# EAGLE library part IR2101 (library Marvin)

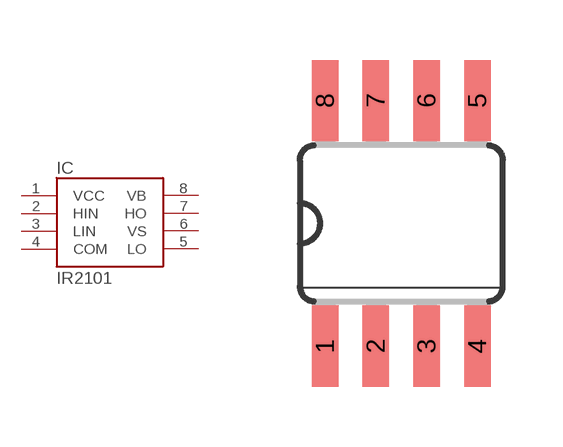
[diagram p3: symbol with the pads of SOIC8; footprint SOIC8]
Designator prefix IC

## IR2101S  [SOIC8]
1  VCC
2  HIN
3  LIN
4  COM
5  LO
6  VS
7  HO
8  VB

## Footprint SOIC8 (pad centres in mm)
smd 0.66 x 2.032: 1 -1.905,-3.073; 2 -0.635,-3.073; 3 0.635,-3.073; 4 1.905,-3.073; 5 1.905,3.073; 6 0.635,3.073; 7 -0.635,3.073; 8 -1.905,3.073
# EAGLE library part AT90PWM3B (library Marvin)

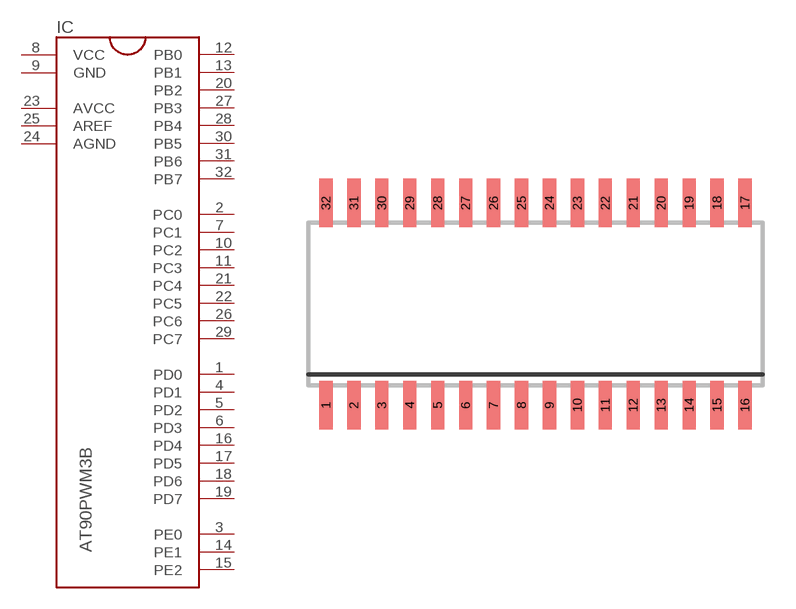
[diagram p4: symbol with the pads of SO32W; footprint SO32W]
Designator prefix IC

## AT90PWM3BS  [SO32W]
1  PD0
2  PC0
3  PE0
4  PD1
5  PD2
6  PD3
7  PC1
8  VCC
9  GND
10  PC2
11  PC3
12  PB0
13  PB1
14  PE1
15  PE2
16  PD4
17  PD5
18  PD6
19  PD7
20  PB2
21  PC4
22  PC5
23  AVCC
24  AGND
25  AREF
26  PC6
27  PB3
28  PB4
29  PC7
30  PB5
31  PB6
32  PB7

## Footprint SO32W (pad centres in mm)
smd 0.6 x 2.2: 1 -9.525,-4.6; 2 -8.255,-4.6; 3 -6.985,-4.6; 4 -5.715,-4.6; 5 -4.445,-4.6; 6 -3.175,-4.6; 7 -1.905,-4.6; 8 -0.635,-4.6; 9 0.635,-4.6; 10 1.905,-4.6; 11 3.175,-4.6; 12 4.445,-4.6; 13 5.715,-4.6; 14 6.985,-4.6; 15 8.255,-4.6; 16 9.525,-4.6; 17 9.525,4.6; 18 8.255,4.6; 19 6.985,4.6; 20 5.715,4.6; 21 4.445,4.6; 22 3.175,4.6; 23 1.905,4.6; 24 0.635,4.6; 25 -0.635,4.6; 26 -1.905,4.6; 27 -3.175,4.6; 28 -4.445,4.6; 29 -5.715,4.6; 30 -6.985,4.6; 31 -8.255,4.6; 32 -9.525,4.6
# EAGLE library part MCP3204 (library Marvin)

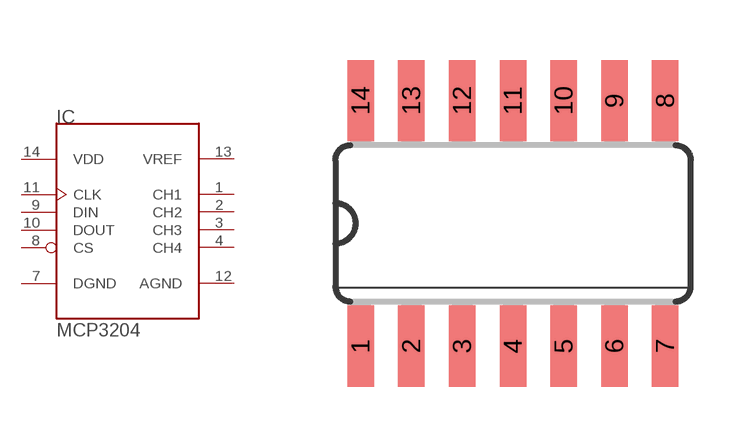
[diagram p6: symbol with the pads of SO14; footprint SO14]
Designator prefix IC

## MCP3204S  [SO14]
1  CH1
2  CH2
3  CH3
4  CH4
7  DGND
8  CS
9  DIN
10  DOUT
11  CLK
12  AGND
13  VREF
14  VDD

## Footprint SO14 (pad centres in mm)
Small Outline package 150 mil
smd 0.66 x 2.032: 1 -3.81,-3.073; 2 -2.54,-3.073; 3 -1.27,-3.073; 4 0,-3.073; 5 1.27,-3.073; 6 2.54,-3.073; 7 3.81,-3.073; 8 3.81,3.073; 9 2.54,3.073; 10 1.27,3.073; 11 0,3.073; 12 -1.27,3.073; 13 -2.54,3.073; 14 -3.81,3.073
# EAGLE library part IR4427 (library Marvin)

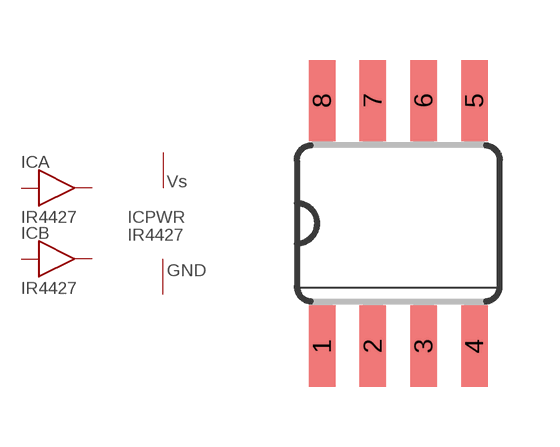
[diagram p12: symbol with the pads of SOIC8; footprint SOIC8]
Designator prefix IC; gates B=IR4427 A=IR4427 PWR=PWR

## IR4427S  [SOIC8]
2  B:IN  in
3  PWR:GND  pwr
4  A:IN  in
5  A:OUT  out
6  PWR:VS  pwr
7  B:OUT  out

## Footprint SOIC8 (pad centres in mm)
smd 0.66 x 2.032: 1 -1.905,-3.073; 2 -0.635,-3.073; 3 0.635,-3.073; 4 1.905,-3.073; 5 1.905,3.073; 6 0.635,3.073; 7 -0.635,3.073; 8 -1.905,3.073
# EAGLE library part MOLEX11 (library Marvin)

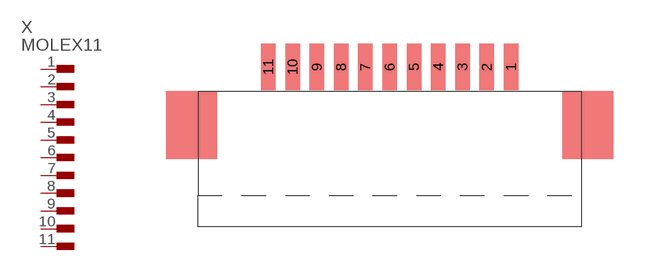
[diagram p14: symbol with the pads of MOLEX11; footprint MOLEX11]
Designator prefix X

## MOLEX11  [MOLEX11]
1  -1
2  -2
3  -3
4  -4
5  -5
6  -6
7  -7
8  -8
9  -9
10  -10
11  -11

## Footprint MOLEX11 (pad centres in mm)
smd 0.6 x 1.9: 1 5,3; 2 4,3; 3 3,3; 4 2,3; 5 1,3; 6 0,3; 7 -1,3; 8 -2,3; 9 -3,3; 10 -4,3; 11 -5,3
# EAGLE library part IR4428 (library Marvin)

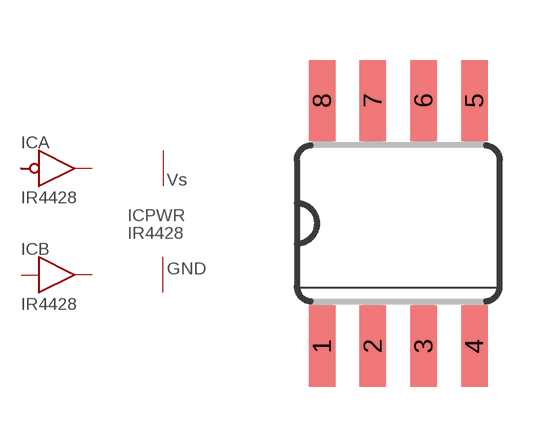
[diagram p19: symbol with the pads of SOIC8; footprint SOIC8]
Designator prefix IC; gates A=AMPN B=AMP PWR=PWR

## IR4428  [SOIC8]
2  A:IN  in
3  PWR:GND  pwr
4  B:IN  in
5  B:OUT  out
6  PWR:VS  pwr
7  A:OUT  out

## Footprint SOIC8 (pad centres in mm)
smd 0.66 x 2.032: 1 -1.905,-3.073; 2 -0.635,-3.073; 3 0.635,-3.073; 4 1.905,-3.073; 5 1.905,3.073; 6 0.635,3.073; 7 -0.635,3.073; 8 -1.905,3.073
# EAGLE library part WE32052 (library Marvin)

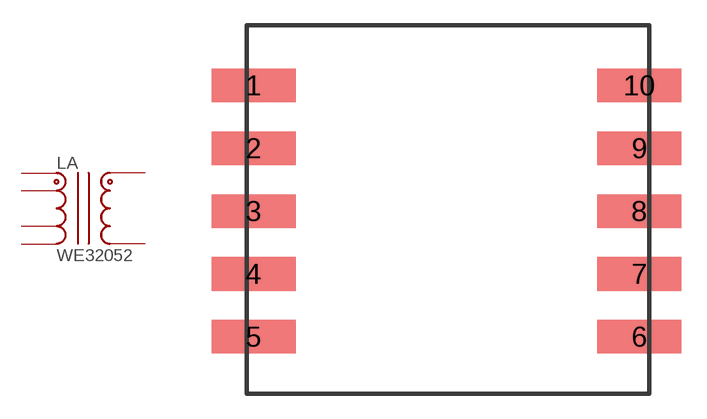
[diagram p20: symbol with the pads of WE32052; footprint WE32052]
Designator prefix L; gates A=FLYBACK-TRANSFORMER B=FLYBACK-TRANSFORMER2

## WE32052  [WE32052]
1  B:1
4  A:4
5  A:5
6  A:6
7  A:7
10  B:10

## Footprint WE32052 (pad centres in mm)
smd 5 x 2: 1 -11.4,7.6; 2 -11.4,3.85; 3 -11.4,0.1; 4 -11.4,-3.65; 5 -11.4,-7.4; 6 11.6,-7.4; 7 11.6,-3.65; 8 11.6,0.1; 9 11.6,3.85; 10 11.6,7.6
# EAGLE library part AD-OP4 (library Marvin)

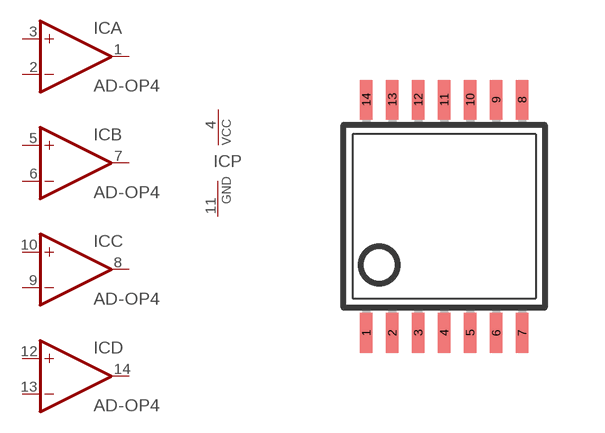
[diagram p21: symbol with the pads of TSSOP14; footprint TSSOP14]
Designator prefix IC; gates A=OP B=OP C=OP D=OP P=PWRGND

## AD-OP4  [TSSOP14]
1  A:OUT  out
2  A:-IN  in
3  A:+IN  in
4  P:VCC  pwr
5  B:+IN  in
6  B:-IN  in
7  B:OUT  out
8  C:OUT  out
9  C:-IN  in
10  C:+IN  in
11  P:GND  pwr
12  D:+IN  in
13  D:-IN  in
14  D:OUT  out

## Footprint TSSOP14 (pad centres in mm)
smd 0.305 x 0.991: 1 -1.95,-2.918; 2 -1.3,-2.918; 3 -0.65,-2.918; 4 0,-2.918; 5 0.65,-2.918; 6 1.3,-2.918; 7 1.95,-2.918; 8 1.95,2.918; 9 1.3,2.918; 10 0.65,2.918; 11 0,2.918; 12 -0.65,2.918; 13 -1.3,2.918; 14 -1.95,2.918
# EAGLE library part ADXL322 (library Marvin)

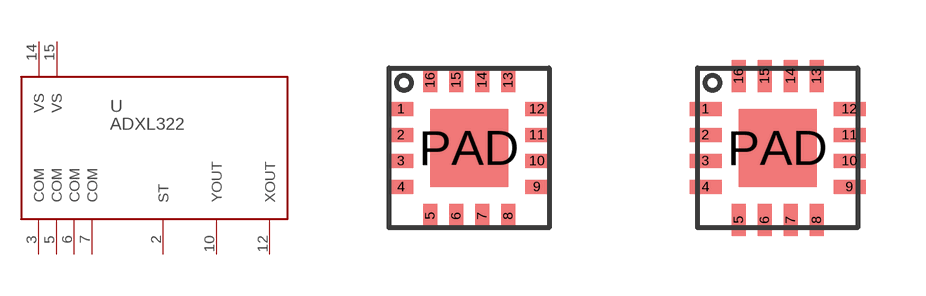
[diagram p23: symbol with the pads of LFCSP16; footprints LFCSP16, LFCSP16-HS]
Designator prefix U

## ADXL322JCP  [LFCSP16]
1  NC  nc
2  ST  in
3  COM  pwr
4  NC  nc
5  COM  pwr
6  COM  pwr
7  COM  pwr
8  NC  nc
9  NC  nc
10  YOUT  out
11  NC  nc
12  XOUT  out
13  NC  nc
14  VS  pwr
15  VS  pwr
16  NC  nc

## ADXL322JCP-HS  [LFCSP16-HS]
Pads as for LFCSP16

## Footprint LFCSP16 (pad centres in mm)
smd 0.6 x 0.35: 1 -1.7,0.975; 2 -1.7,0.325; 3 -1.7,-0.325; 4 -1.7,-0.975; 9 1.7,-0.975; 10 1.7,-0.325; 11 1.7,0.325; 12 1.7,0.975
smd 0.35 x 0.6: 5 -0.975,-1.7; 6 -0.325,-1.7; 7 0.325,-1.7; 8 0.975,-1.7; 13 0.975,1.7; 14 0.325,1.7; 15 -0.325,1.7; 16 -0.975,1.7
smd 1.95 x 1.95: PAD 0,0

## Footprint LFCSP16-HS (pad centres in mm)
smd 0.8 x 0.35: 1 -1.8,0.975; 2 -1.8,0.325; 3 -1.8,-0.325; 4 -1.8,-0.975; 9 1.8,-0.975; 10 1.8,-0.325; 11 1.8,0.325; 12 1.8,0.975
smd 0.35 x 0.8: 5 -0.975,-1.8; 6 -0.325,-1.8; 7 0.325,-1.8; 8 0.975,-1.8; 13 0.975,1.8; 14 0.325,1.8; 15 -0.325,1.8; 16 -0.975,1.8
smd 1.95 x 1.95: PAD 0,0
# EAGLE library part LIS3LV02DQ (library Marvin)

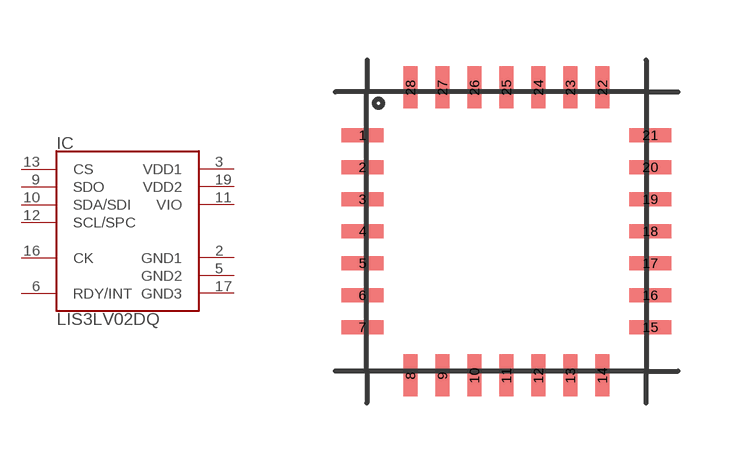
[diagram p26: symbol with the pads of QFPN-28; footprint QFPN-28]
Designator prefix IC

## LIS3LV02DQ  [QFPN-28]
2  GND1
3  VDD1
5  GND2
6  RDY/INT
9  SDO
10  SDA/SDI
11  VIO
12  SCL/SPC
13  CS
16  CK
17  GND3
19  VDD2

## Footprint QFPN-28 (pad centres in mm)
smd 1.05 x 0.35: 1 -3.6,2.4; 2 -3.6,1.6; 3 -3.6,0.8; 4 -3.6,0; 5 -3.6,-0.8; 6 -3.6,-1.6; 7 -3.6,-2.4; 15 3.6,-2.4; 16 3.6,-1.6; 17 3.6,-0.8; 18 3.6,0; 19 3.6,0.8; 20 3.6,1.6; 21 3.6,2.4
smd 0.35 x 1.05: 8 -2.4,-3.6; 9 -1.6,-3.6; 10 -0.8,-3.6; 11 0,-3.6; 12 0.8,-3.6; 13 1.6,-3.6; 14 2.4,-3.6; 22 2.4,3.6; 23 1.6,3.6; 24 0.8,3.6; 25 0,3.6; 26 -0.8,3.6; 27 -1.6,3.6; 28 -2.4,3.6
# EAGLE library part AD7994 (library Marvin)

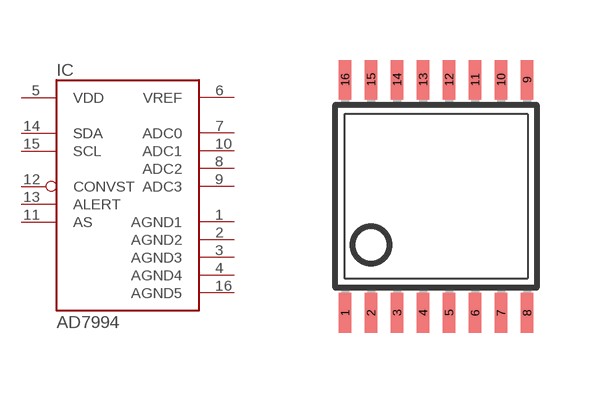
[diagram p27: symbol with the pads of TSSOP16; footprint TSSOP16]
Designator prefix IC

## AD7994  [TSSOP16]
1  AGND1
2  AGND2
3  AGND3
4  AGND4
5  VDD
6  VREF
7  ADC0
8  ADC2
9  ADC3
10  ADC1
11  AS
12  CONVST
13  ALERT
14  SDA
15  SCL
16  AGND5

## Footprint TSSOP16 (pad centres in mm)
smd 0.305 x 0.991: 1 -2.275,-2.918; 2 -1.625,-2.918; 3 -0.975,-2.918; 4 -0.325,-2.918; 5 0.325,-2.918; 6 0.975,-2.918; 7 1.625,-2.918; 8 2.275,-2.918; 9 2.275,2.918; 10 1.625,2.918; 11 0.975,2.918; 12 0.325,2.918; 13 -0.325,2.918; 14 -0.975,2.918; 15 -1.625,2.918; 16 -2.275,2.918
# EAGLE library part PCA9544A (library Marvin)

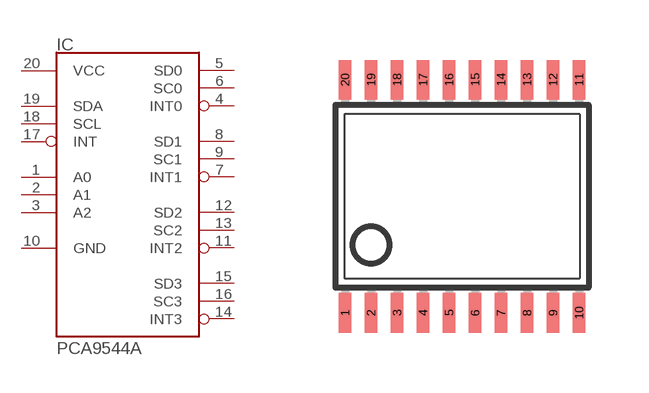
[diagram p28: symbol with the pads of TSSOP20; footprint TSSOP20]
Designator prefix IC

## PCA9544A  [TSSOP20]
1  A0
2  A1
3  A2
4  INT0
5  SD0
6  SC0
7  INT1
8  SD1
9  SC1
10  GND
11  INT2
12  SD2
13  SC2
14  INT3
15  SD3
16  SC3
17  INT
18  SCL
19  SDA
20  VCC

## Footprint TSSOP20 (pad centres in mm)
Thin Shrink Small Outline Plastic 20 MAX3223-MAX3243.pdf
smd 0.305 x 0.991: 1 -2.925,-2.918; 2 -2.275,-2.918; 3 -1.625,-2.918; 4 -0.975,-2.918; 5 -0.325,-2.918; 6 0.325,-2.918; 7 0.975,-2.918; 8 1.625,-2.918; 9 2.275,-2.918; 10 2.925,-2.918; 11 2.925,2.918; 12 2.275,2.918; 13 1.625,2.918; 14 0.975,2.918; 15 0.325,2.918; 16 -0.325,2.918; 17 -0.975,2.918; 18 -1.625,2.918; 19 -2.275,2.918; 20 -2.925,2.918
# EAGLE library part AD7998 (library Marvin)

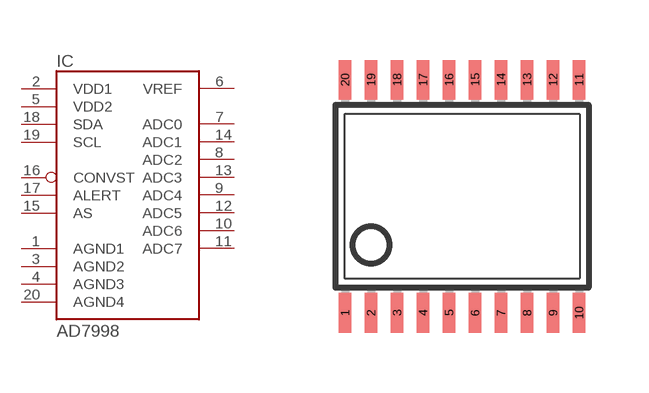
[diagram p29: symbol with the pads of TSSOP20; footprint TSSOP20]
Designator prefix IC

## AD7998  [TSSOP20]
1  AGND1
2  VDD1
3  AGND2
4  AGND3
5  VDD2
6  VREF
7  ADC0
8  ADC2
9  ADC4
10  ADC6
11  ADC7
12  ADC5
13  ADC3
14  ADC1
15  AS
16  CONVST
17  ALERT
18  SDA
19  SCL
20  AGND4

## Footprint TSSOP20 (pad centres in mm)
Thin Shrink Small Outline Plastic 20 MAX3223-MAX3243.pdf
smd 0.305 x 0.991: 1 -2.925,-2.918; 2 -2.275,-2.918; 3 -1.625,-2.918; 4 -0.975,-2.918; 5 -0.325,-2.918; 6 0.325,-2.918; 7 0.975,-2.918; 8 1.625,-2.918; 9 2.275,-2.918; 10 2.925,-2.918; 11 2.925,2.918; 12 2.275,2.918; 13 1.625,2.918; 14 0.975,2.918; 15 0.325,2.918; 16 -0.325,2.918; 17 -0.975,2.918; 18 -1.625,2.918; 19 -2.275,2.918; 20 -2.925,2.918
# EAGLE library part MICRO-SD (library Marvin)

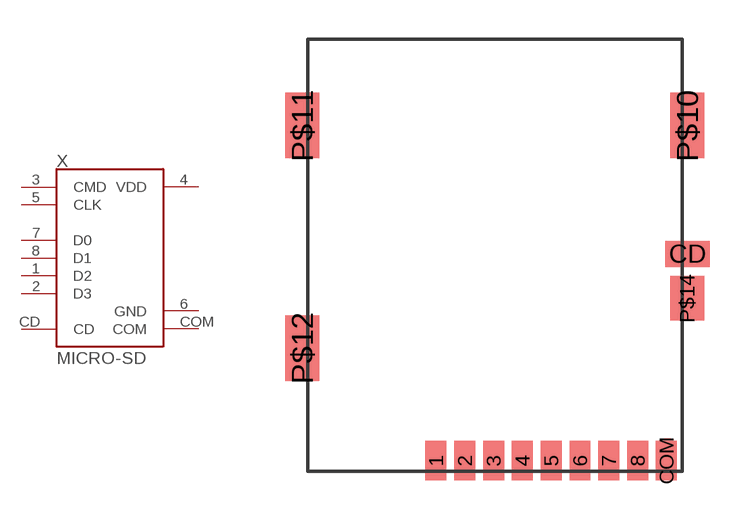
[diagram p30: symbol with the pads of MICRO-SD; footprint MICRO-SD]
Designator prefix X

## MICRO-SD  [MICRO-SD]
1  D2
2  D3
3  CMD
4  VDD
5  CLK
6  GND
7  D0
8  D1
CD  CD
COM  COM

## Footprint MICRO-SD (pad centres in mm)
smd 0.8 x 1.5: 1 4.9,0.4; 2 6,0.4; 3 7.1,0.4; 4 8.2,0.4; 5 9.3,0.4; 6 10.4,0.4; 7 11.5,0.4; 8 12.6,0.4; COM 13.7,0.4
smd 1.7 x 1: CD 14.5,8.3
smd 1.3 x 2.5: P$10 14.5,13.2; P$11 -0.2,13.2; P$12 -0.2,4.7
smd 1.3 x 1.7: P$14 14.5,6.6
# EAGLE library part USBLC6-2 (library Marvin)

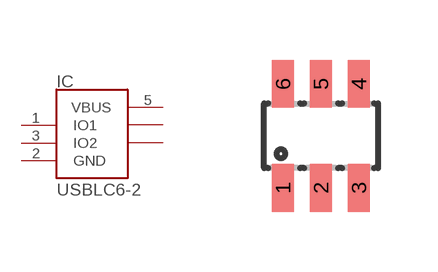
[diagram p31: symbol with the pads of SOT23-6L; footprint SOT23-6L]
Designator prefix IC

## USBLC6-2  [SOT23-6L]
1  IO1
2  GND
3  IO2
4  IO2B
5  VBUS
6  IO1B

## Footprint SOT23-6L (pad centres in mm)
Small Outline Transistor
smd 0.55 x 1.2: 1 -0.95,-1.3; 2 0,-1.3; 3 0.95,-1.3; 4 0.95,1.3; 5 0,1.3; 6 -0.95,1.3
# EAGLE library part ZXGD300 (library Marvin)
ZXGD300 IGBT Driver

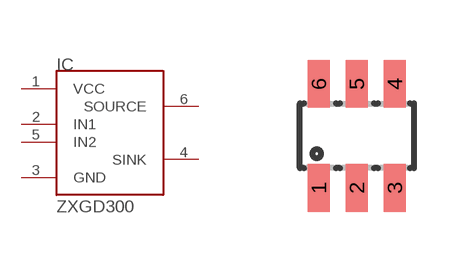
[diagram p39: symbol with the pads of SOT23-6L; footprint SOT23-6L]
Designator prefix IC

## ZXGD300  [SOT23-6L]
1  VCC  pwr
2  IN1
3  GND  pwr
4  SINK
5  IN2
6  SOURCE

## Footprint SOT23-6L (pad centres in mm)
Small Outline Transistor
smd 0.55 x 1.2: 1 -0.95,-1.3; 2 0,-1.3; 3 0.95,-1.3; 4 0.95,1.3; 5 0,1.3; 6 -0.95,1.3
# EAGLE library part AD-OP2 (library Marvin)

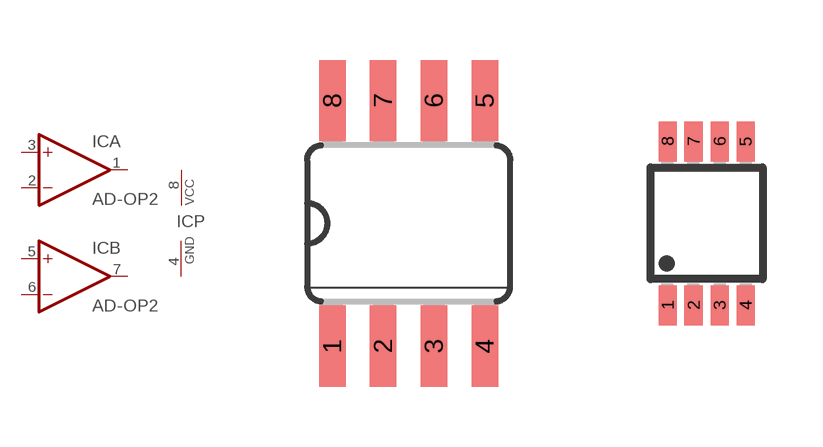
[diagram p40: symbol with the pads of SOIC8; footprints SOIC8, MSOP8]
Designator prefix IC; gates P=PWRGND A=OP B=OP

## AD-OP2S  [SOIC8]
1  A:OUT  out
2  A:-IN  in
3  A:+IN  in
4  P:GND  pwr
5  B:+IN  in
6  B:-IN  in
7  B:OUT  out
8  P:VCC  pwr

## AD-OP2M  [MSOP8]
Pads as for SOIC8

## Footprint SOIC8 (pad centres in mm)
smd 0.66 x 2.032: 1 -1.905,-3.073; 2 -0.635,-3.073; 3 0.635,-3.073; 4 1.905,-3.073; 5 1.905,3.073; 6 0.635,3.073; 7 -0.635,3.073; 8 -1.905,3.073

## Footprint MSOP8 (pad centres in mm)
smd 0.45 x 1: 1 -0.975,-2.05; 2 -0.325,-2.05; 3 0.325,-2.05; 4 0.975,-2.05; 5 0.975,2.05; 6 0.325,2.05; 7 -0.325,2.05; 8 -0.975,2.05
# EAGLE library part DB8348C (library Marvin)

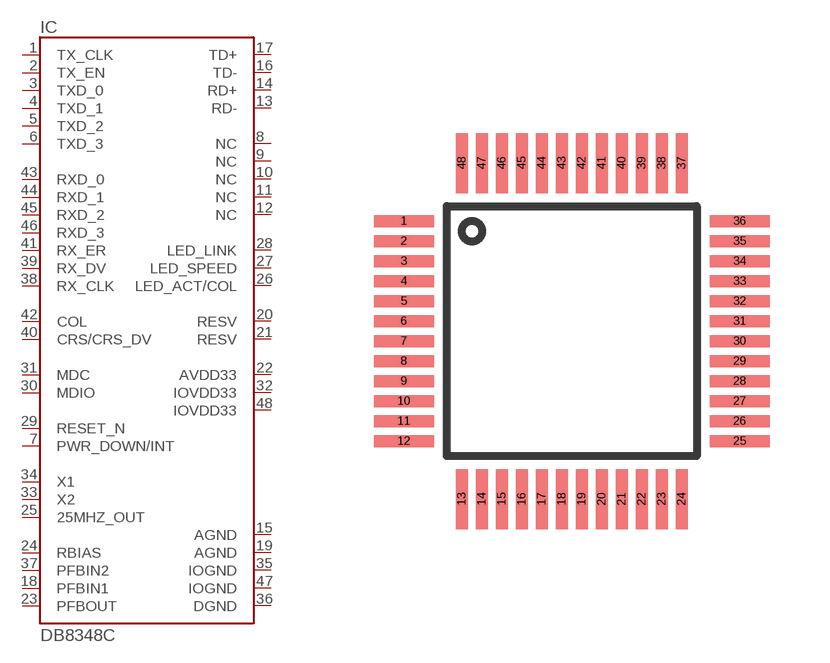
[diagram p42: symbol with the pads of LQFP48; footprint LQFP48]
Designator prefix IC

## DB8348C  [LQFP48]
1  TX_CLK
2  TX_EN
3  TXD_0
4  TXD_1
5  TXD_2
6  TXD_3
7  PWR_DOWN/INT
8  NC
9  NC
10  NC
11  NC
12  NC
13  RD-
14  RD+
15  AGND
16  TD-
17  TD+
18  PFBIN1
19  AGND
20  RESV
21  RESV
22  AVDD33
23  PFBOUT
24  RBIAS
25  25MHZ_OUT
26  LED_ACT/COL
27  LED_SPEED
28  LED_LINK
29  RESET_N
30  MDIO
31  MDC
32  IOVDD33
33  X2
34  X1
35  IOGND
36  DGND
37  PFBIN2
38  RX_CLK
39  RX_DV
40  CRS/CRS_DV
41  RX_ER
42  COL
43  RXD_0
44  RXD_1
45  RXD_2
46  RXD_3
47  IOGND
48  IOVDD33

## Footprint LQFP48 (pad centres in mm)
smd 1.5 x 0.3: 1 -4.2,2.75; 2 -4.2,2.25; 3 -4.2,1.75; 4 -4.2,1.25; 5 -4.2,0.75; 6 -4.2,0.25; 7 -4.2,-0.25; 8 -4.2,-0.75; 9 -4.2,-1.25; 10 -4.2,-1.75; 11 -4.2,-2.25; 12 -4.2,-2.75; 25 4.2,-2.75; 26 4.2,-2.25; 27 4.2,-1.75; 28 4.2,-1.25; 29 4.2,-0.75; 30 4.2,-0.25; 31 4.2,0.25; 32 4.2,0.75; 33 4.2,1.25; 34 4.2,1.75; 35 4.2,2.25; 36 4.2,2.75
smd 0.3 x 1.5: 13 -2.75,-4.2; 14 -2.25,-4.2; 15 -1.75,-4.2; 16 -1.25,-4.2; 17 -0.75,-4.2; 18 -0.25,-4.2; 19 0.25,-4.2; 20 0.75,-4.2; 21 1.25,-4.2; 22 1.75,-4.2; 23 2.25,-4.2; 24 2.75,-4.2; 37 2.75,4.2; 38 2.25,4.2; 39 1.75,4.2; 40 1.25,4.2; 41 0.75,4.2; 42 0.25,4.2; 43 -0.25,4.2; 44 -0.75,4.2; 45 -1.25,4.2; 46 -1.75,4.2; 47 -2.25,4.2; 48 -2.75,4.2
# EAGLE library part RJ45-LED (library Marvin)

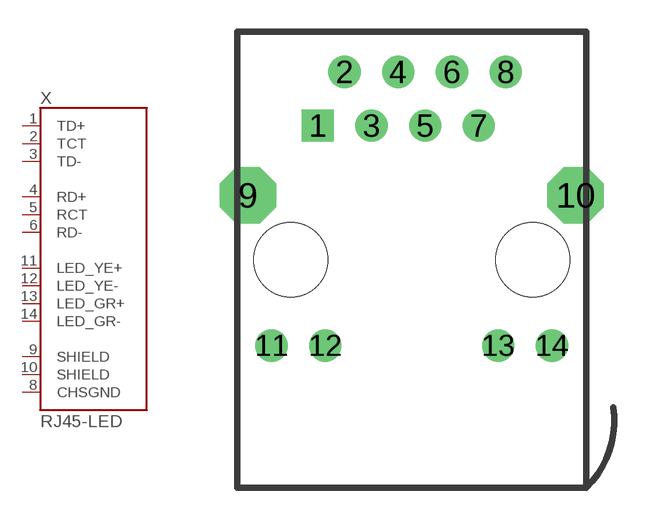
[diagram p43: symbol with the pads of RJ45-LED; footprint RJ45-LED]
Designator prefix X

## RJ45-LED  [RJ45-LED]
1  TD+
2  TCT
3  TD-
4  RD+
5  RCT
6  RD-
8  CHSGND
9  SHIELD
10  SHIELD
11  LED_YE+
12  LED_YE-
13  LED_GR+
14  LED_GR-

## Footprint RJ45-LED (pad centres in mm)
RJ45-Ethernet Jack with inductors Stewart Connector - SI-60062-F
drill 1.016 square: 1 -4.445,6.35
drill 1.016 round: 2 -3.175,8.89; 3 -1.905,6.35; 4 -0.635,8.89; 5 0.635,6.35; 6 1.905,8.89; 7 3.175,6.35; 8 4.445,8.89; 11 -6.629,-4.064; 12 -4.089,-4.064; 13 4.089,-4.064; 14 6.629,-4.064
drill 1.778 octagon: 9 -7.747,3.048; 10 7.747,3.048
hole 3.5 at -5.715,0
hole 3.5 at 5.715,0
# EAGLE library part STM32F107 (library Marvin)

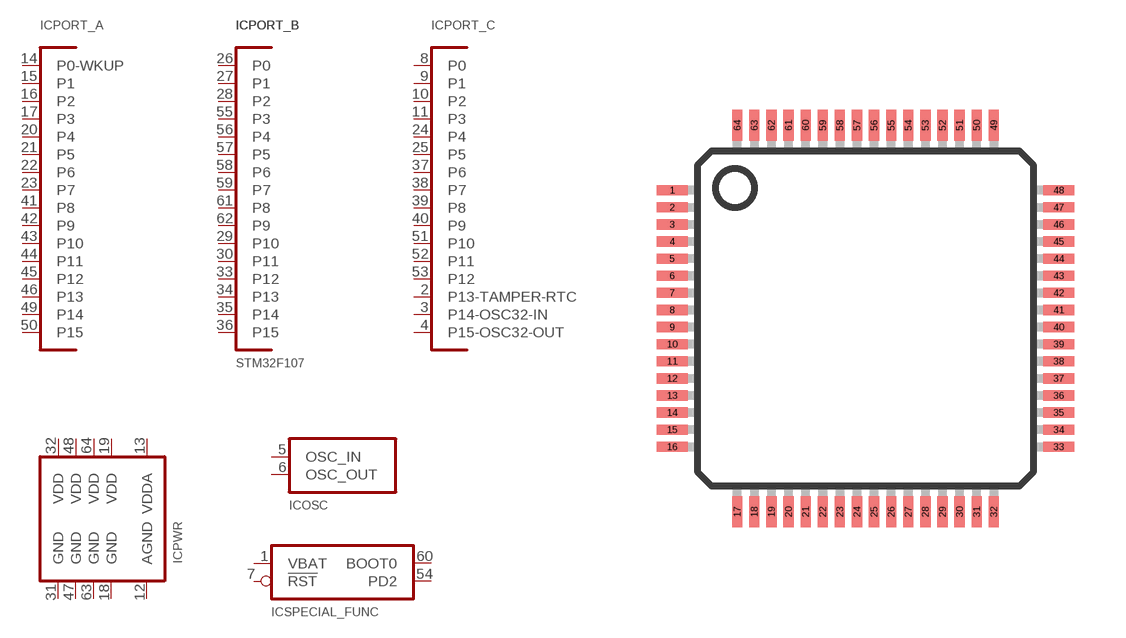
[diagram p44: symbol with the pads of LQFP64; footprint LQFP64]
Designator prefix IC; gates PORT_A=IO_PORT_A PORT_B=IO_PORT PORT_C=IO_PORT_C OSC=OSC PWR=DIG_PWR4 SPECIAL_FUNC=SPECIAL_FUNCD

## STM32F107R  [LQFP64]
1  SPECIAL_FUNC:VBAT  pas
2  PORT_C:P13-TAMPER-RTC
3  PORT_C:P14-OSC32-IN
4  PORT_C:P15-OSC32-OUT
5  OSC:OSC_IN  pas
6  OSC:OSC_OUT  pas
7  SPECIAL_FUNC:!RST  in
8  PORT_C:P0
9  PORT_C:P1
10  PORT_C:P2
11  PORT_C:P3
12  PWR:AGND  pwr
13  PWR:VDDA  pwr
14  PORT_A:P0-WKUP
15  PORT_A:P1
16  PORT_A:P2
17  PORT_A:P3
18  PWR:GND  pwr
19  PWR:VDD  pwr
20  PORT_A:P4
21  PORT_A:P5
22  PORT_A:P6
23  PORT_A:P7
24  PORT_C:P4
25  PORT_C:P5
26  PORT_B:P0
27  PORT_B:P1
28  PORT_B:P2
29  PORT_B:P10
30  PORT_B:P11
31  PWR:GND  pwr
32  PWR:VDD  pwr
33  PORT_B:P12
34  PORT_B:P13
35  PORT_B:P14
36  PORT_B:P15
37  PORT_C:P6
38  PORT_C:P7
39  PORT_C:P8
40  PORT_C:P9
41  PORT_A:P8
42  PORT_A:P9
43  PORT_A:P10
44  PORT_A:P11
45  PORT_A:P12
46  PORT_A:P13
47  PWR:GND  pwr
48  PWR:VDD  pwr
49  PORT_A:P14
50  PORT_A:P15
51  PORT_C:P10
52  PORT_C:P11
53  PORT_C:P12
54  SPECIAL_FUNC:PD2
55  PORT_B:P3
56  PORT_B:P4
57  PORT_B:P5
58  PORT_B:P6
59  PORT_B:P7
60  SPECIAL_FUNC:BOOT0  in
61  PORT_B:P8
62  PORT_B:P9
63  PWR:GND  pwr
64  PWR:VDD  pwr

## Footprint LQFP64 (pad centres in mm)
64-Lead Low Profile Quad Flat Package [LQFP] (ST-64-2) COMPLIANT TO JEDEC STANDARDS MS-026-BCD Source: http://www.analog.com/UploadedFiles/Data_Sheets/288945048AD7C7019_20_1_2_4_5_6_7_0.pdf
smd 0.9 x 0.3: 1 -5.65,3.75; 2 -5.65,3.25; 3 -5.65,2.75; 4 -5.65,2.25; 5 -5.65,1.75; 6 -5.65,1.25; 7 -5.65,0.75; 8 -5.65,0.25; 9 -5.65,-0.25; 10 -5.65,-0.75; 11 -5.65,-1.25; 12 -5.65,-1.75; 13 -5.65,-2.25; 14 -5.65,-2.75; 15 -5.65,-3.25; 16 -5.65,-3.75; 33 5.65,-3.75; 34 5.65,-3.25; 35 5.65,-2.75; 36 5.65,-2.25; 37 5.65,-1.75; 38 5.65,-1.25; 39 5.65,-0.75; 40 5.65,-0.25; 41 5.65,0.25; 42 5.65,0.75; 43 5.65,1.25; 44 5.65,1.75; 45 5.65,2.25; 46 5.65,2.75; 47 5.65,3.25; 48 5.65,3.75
smd 0.3 x 0.9: 17 -3.75,-5.65; 18 -3.25,-5.65; 19 -2.75,-5.65; 20 -2.25,-5.65; 21 -1.75,-5.65; 22 -1.25,-5.65; 23 -0.75,-5.65; 24 -0.25,-5.65; 25 0.25,-5.65; 26 0.75,-5.65; 27 1.25,-5.65; 28 1.75,-5.65; 29 2.25,-5.65; 30 2.75,-5.65; 31 3.25,-5.65; 32 3.75,-5.65; 49 3.75,5.65; 50 3.25,5.65; 51 2.75,5.65; 52 2.25,5.65; 53 1.75,5.65; 54 1.25,5.65; 55 0.75,5.65; 56 0.25,5.65; 57 -0.25,5.65; 58 -0.75,5.65; 59 -1.25,5.65; 60 -1.75,5.65; 61 -2.25,5.65; 62 -2.75,5.65; 63 -3.25,5.65; 64 -3.75,5.65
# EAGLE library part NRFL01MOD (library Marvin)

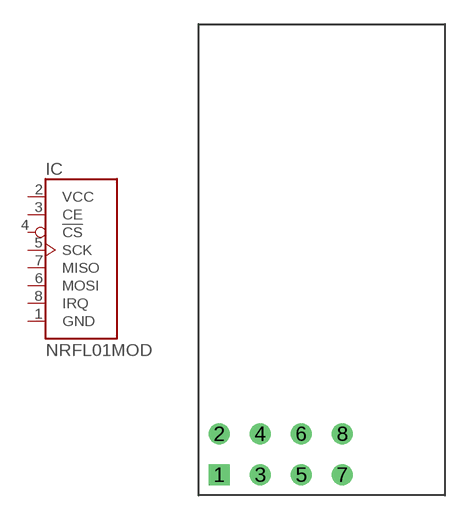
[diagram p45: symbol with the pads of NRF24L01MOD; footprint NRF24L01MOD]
Designator prefix IC

## NRFL01MOD  [NRF24L01MOD]
1  GND  pwr
2  VCC  pwr
3  CE
4  !CS
5  SCK
6  MOSI
7  MISO
8  IRQ

## Footprint NRF24L01MOD (pad centres in mm)
drill 0.8 square: 1 0,0
drill 0.8 round: 2 0,2.54; 3 2.54,0; 4 2.54,2.54; 5 5.08,0; 6 5.08,2.54; 7 7.62,0; 8 7.62,2.54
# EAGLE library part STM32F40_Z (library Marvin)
168 MHz, 192KB RAM, 1024 KB Flash

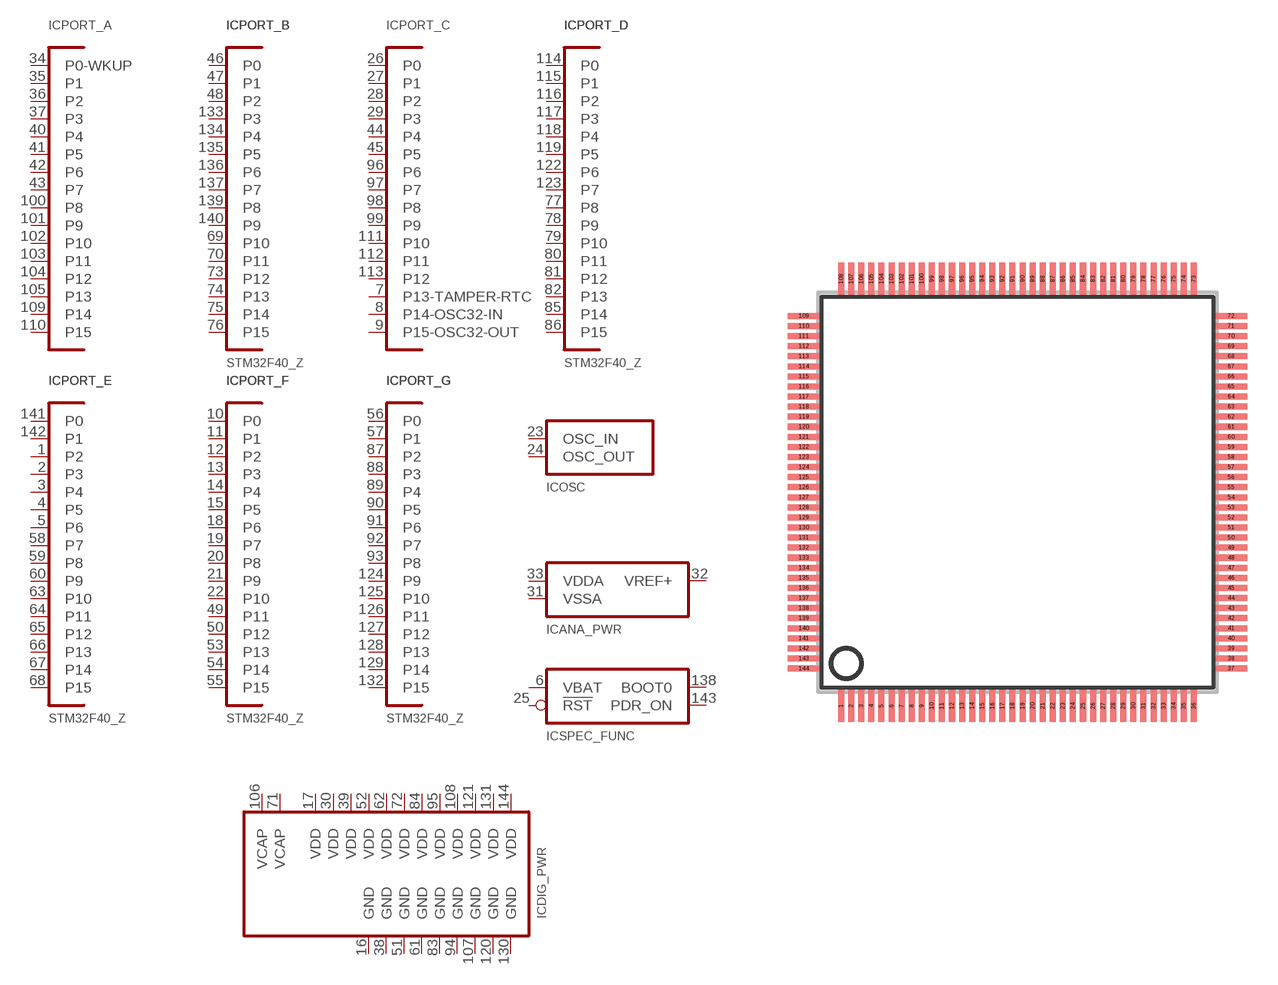
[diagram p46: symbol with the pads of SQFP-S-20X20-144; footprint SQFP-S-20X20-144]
Designator prefix IC; gates PORT_A=IO_PORT_A PORT_C=IO_PORT_C PORT_B=IO_PORT PORT_D=IO_PORT PORT_E=IO_PORT PORT_F=IO_PORT PORT_G=IO_PORT OSC=OSC ANA_PWR=ANA_PWR40_Z DIG_PWR=DIG_PWR40_Z SPEC_FUNC=SPEC_FUNC40X

## STM32F40_Z  [SQFP-S-20X20-144]
1  PORT_E:P2
2  PORT_E:P3
3  PORT_E:P4
4  PORT_E:P5
5  PORT_E:P6
6  SPEC_FUNC:VBAT  pas
7  PORT_C:P13-TAMPER-RTC
8  PORT_C:P14-OSC32-IN
9  PORT_C:P15-OSC32-OUT
10  PORT_F:P0
11  PORT_F:P1
12  PORT_F:P2
13  PORT_F:P3
14  PORT_F:P4
15  PORT_F:P5
16  DIG_PWR:GND  pwr
17  DIG_PWR:VDD  pwr
18  PORT_F:P6
19  PORT_F:P7
20  PORT_F:P8
21  PORT_F:P9
22  PORT_F:P10
23  OSC:OSC_IN  pas
24  OSC:OSC_OUT  pas
25  SPEC_FUNC:!RST  in
26  PORT_C:P0
27  PORT_C:P1
28  PORT_C:P2
29  PORT_C:P3
30  DIG_PWR:VDD  pwr
31  ANA_PWR:VSSA  pwr
32  ANA_PWR:VREF+  pas
33  ANA_PWR:VDDA  pwr
34  PORT_A:P0-WKUP
35  PORT_A:P1
36  PORT_A:P2
37  PORT_A:P3
38  DIG_PWR:GND  pwr
39  DIG_PWR:VDD  pwr
40  PORT_A:P4
41  PORT_A:P5
42  PORT_A:P6
43  PORT_A:P7
44  PORT_C:P4
45  PORT_C:P5
46  PORT_B:P0
47  PORT_B:P1
48  PORT_B:P2
49  PORT_F:P11
50  PORT_F:P12
51  DIG_PWR:GND  pwr
52  DIG_PWR:VDD  pwr
53  PORT_F:P13
54  PORT_F:P14
55  PORT_F:P15
56  PORT_G:P0
57  PORT_G:P1
58  PORT_E:P7
59  PORT_E:P8
60  PORT_E:P9
61  DIG_PWR:GND  pwr
62  DIG_PWR:VDD  pwr
63  PORT_E:P10
64  PORT_E:P11
65  PORT_E:P12
66  PORT_E:P13
67  PORT_E:P14
68  PORT_E:P15
69  PORT_B:P10
70  PORT_B:P11
71  DIG_PWR:VCAP  pwr
72  DIG_PWR:VDD  pwr
73  PORT_B:P12
74  PORT_B:P13
75  PORT_B:P14
76  PORT_B:P15
77  PORT_D:P8
78  PORT_D:P9
79  PORT_D:P10
80  PORT_D:P11
81  PORT_D:P12
82  PORT_D:P13
83  DIG_PWR:GND  pwr
84  DIG_PWR:VDD  pwr
85  PORT_D:P14
86  PORT_D:P15
87  PORT_G:P2
88  PORT_G:P3
89  PORT_G:P4
90  PORT_G:P5
91  PORT_G:P6
92  PORT_G:P7
93  PORT_G:P8
94  DIG_PWR:GND  pwr
95  DIG_PWR:VDD  pwr
96  PORT_C:P6
97  PORT_C:P7
98  PORT_C:P8
99  PORT_C:P9
100  PORT_A:P8
101  PORT_A:P9
102  PORT_A:P10
103  PORT_A:P11
104  PORT_A:P12
105  PORT_A:P13
106  DIG_PWR:VCAP  pwr
107  DIG_PWR:GND  pwr
108  DIG_PWR:VDD  pwr
109  PORT_A:P14
110  PORT_A:P15
111  PORT_C:P10
112  PORT_C:P11
113  PORT_C:P12
114  PORT_D:P0
115  PORT_D:P1
116  PORT_D:P2
117  PORT_D:P3
118  PORT_D:P4
119  PORT_D:P5
120  DIG_PWR:GND  pwr
121  DIG_PWR:VDD  pwr
122  PORT_D:P6
123  PORT_D:P7
124  PORT_G:P9
125  PORT_G:P10
126  PORT_G:P11
127  PORT_G:P12
128  PORT_G:P13
129  PORT_G:P14
130  DIG_PWR:GND  pwr
131  DIG_PWR:VDD  pwr
132  PORT_G:P15
133  PORT_B:P3
134  PORT_B:P4
135  PORT_B:P5
136  PORT_B:P6
137  PORT_B:P7
138  SPEC_FUNC:BOOT0  in
139  PORT_B:P8
140  PORT_B:P9
141  PORT_E:P0
142  PORT_E:P1
143  SPEC_FUNC:PDR_ON
144  DIG_PWR:VDD  pwr

## Footprint SQFP-S-20X20-144 (pad centres in mm)
QFP144 shrink quad flat pack, square
smd 0.3 x 1.6: 1 -8.75,-10.6; 2 -8.25,-10.6; 3 -7.75,-10.6; 4 -7.25,-10.6; 5 -6.75,-10.6; 6 -6.25,-10.6; 7 -5.75,-10.6; 8 -5.25,-10.6; 9 -4.75,-10.6; 10 -4.25,-10.6; 11 -3.75,-10.6; 12 -3.25,-10.6; 13 -2.75,-10.6; 14 -2.25,-10.6; 15 -1.75,-10.6; 16 -1.25,-10.6; 17 -0.75,-10.6; 18 -0.25,-10.6; 19 0.25,-10.6; 20 0.75,-10.6; 21 1.25,-10.6; 22 1.75,-10.6; 23 2.25,-10.6; 24 2.75,-10.6; 25 3.25,-10.6; 26 3.75,-10.6; 27 4.25,-10.6; 28 4.75,-10.6; 29 5.25,-10.6; 30 5.75,-10.6; 31 6.25,-10.6; 32 6.75,-10.6; 33 7.25,-10.6; 34 7.75,-10.6; 35 8.25,-10.6; 36 8.75,-10.6; 73 8.75,10.6; 74 8.25,10.6; 75 7.75,10.6; 76 7.25,10.6; 77 6.75,10.6; 78 6.25,10.6; 79 5.75,10.6; 80 5.25,10.6; 81 4.75,10.6; 82 4.25,10.6; 83 3.75,10.6; 84 3.25,10.6; 85 2.75,10.6; 86 2.25,10.6; 87 1.75,10.6; 88 1.25,10.6; 89 0.75,10.6; 90 0.25,10.6; 91 -0.25,10.6; 92 -0.75,10.6; 93 -1.25,10.6; 94 -1.75,10.6; 95 -2.25,10.6; 96 -2.75,10.6; 97 -3.25,10.6; 98 -3.75,10.6; 99 -4.25,10.6; 100 -4.75,10.6; 101 -5.25,10.6; 102 -5.75,10.6; 103 -6.25,10.6; 104 -6.75,10.6; 105 -7.25,10.6; 106 -7.75,10.6; 107 -8.25,10.6; 108 -8.75,10.6
smd 1.6 x 0.3: 37 10.6,-8.75; 38 10.6,-8.25; 39 10.6,-7.75; 40 10.6,-7.25; 41 10.6,-6.75; 42 10.6,-6.25; 43 10.6,-5.75; 44 10.6,-5.25; 45 10.6,-4.75; 46 10.6,-4.25; 47 10.6,-3.75; 48 10.6,-3.25; 49 10.6,-2.75; 50 10.6,-2.25; 51 10.6,-1.75; 52 10.6,-1.25; 53 10.6,-0.75; 54 10.6,-0.25; 55 10.6,0.25; 56 10.6,0.75; 57 10.6,1.25; 58 10.6,1.75; 59 10.6,2.25; 60 10.6,2.75; 61 10.6,3.25; 62 10.6,3.75; 63 10.6,4.25; 64 10.6,4.75; 65 10.6,5.25; 66 10.6,5.75; 67 10.6,6.25; 68 10.6,6.75; 69 10.6,7.25; 70 10.6,7.75; 71 10.6,8.25; 72 10.6,8.75; 109 -10.6,8.75; 110 -10.6,8.25; 111 -10.6,7.75; 112 -10.6,7.25; 113 -10.6,6.75; 114 -10.6,6.25; 115 -10.6,5.75; 116 -10.6,5.25; 117 -10.6,4.75; 118 -10.6,4.25; 119 -10.6,3.75; 120 -10.6,3.25; 121 -10.6,2.75; 122 -10.6,2.25; 123 -10.6,1.75; 124 -10.6,1.25; 125 -10.6,0.75; 126 -10.6,0.25; 127 -10.6,-0.25; 128 -10.6,-0.75; 129 -10.6,-1.25; 130 -10.6,-1.75; 131 -10.6,-2.25; 132 -10.6,-2.75; 133 -10.6,-3.25; 134 -10.6,-3.75; 135 -10.6,-4.25; 136 -10.6,-4.75; 137 -10.6,-5.25; 138 -10.6,-5.75; 139 -10.6,-6.25; 140 -10.6,-6.75; 141 -10.6,-7.25; 142 -10.6,-7.75; 143 -10.6,-8.25; 144 -10.6,-8.75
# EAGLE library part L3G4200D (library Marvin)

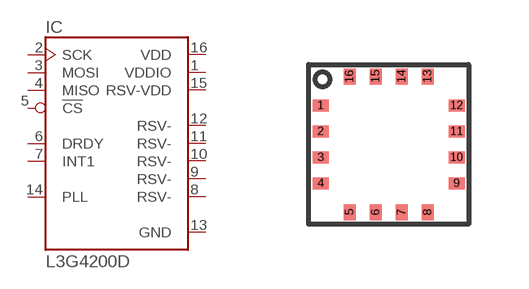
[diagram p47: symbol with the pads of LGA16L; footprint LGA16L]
Designator prefix IC

## L3G4200D  [LGA16L]
1  VDDIO  pwr
2  SCK
3  MOSI
4  MISO
5  !CS
6  DRDY
7  INT1
8  RSV-  pas
9  RSV-  pas
10  RSV-  pas
11  RSV-  pas
12  RSV-  pas
13  GND  pwr
14  PLL
15  RSV-VDD  pas
16  VDD  pwr

## Footprint LGA16L (pad centres in mm)
smd 0.4 x 0.3: 1 -1.7,0.975; 2 -1.7,0.325; 3 -1.7,-0.325; 4 -1.7,-0.975; 9 1.7,-0.975; 10 1.7,-0.325; 11 1.7,0.325; 12 1.7,0.975
smd 0.3 x 0.4: 5 -0.975,-1.7; 6 -0.325,-1.7; 7 0.325,-1.7; 8 0.975,-1.7; 13 0.975,1.7; 14 0.325,1.7; 15 -0.325,1.7; 16 -0.975,1.7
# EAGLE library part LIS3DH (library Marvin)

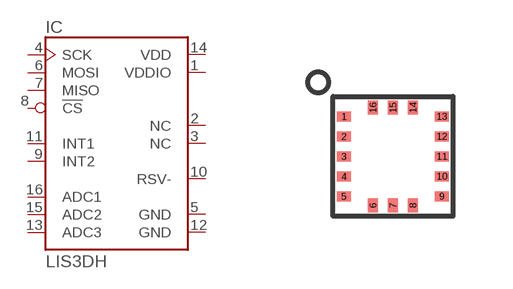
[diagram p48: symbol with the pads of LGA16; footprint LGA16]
Designator prefix IC

## LIS3DH  [LGA16]
1  VDDIO  pwr
2  NC  pas
3  NC  pas
4  SCK
5  GND  pas
6  MOSI
7  MISO
8  !CS
9  INT2
10  RSV-  pas
11  INT1
12  GND  pwr
13  ADC3  pas
14  VDD  pwr
15  ADC2  pas
16  ADC1

## Footprint LGA16 (pad centres in mm)
smd 0.35 x 0.25: 1 -1.225,1; 2 -1.225,0.5; 3 -1.225,0; 4 -1.225,-0.5; 5 -1.225,-1; 9 1.225,-0.995; 10 1.225,-0.495; 11 1.225,0.005; 12 1.225,0.505; 13 1.225,1.005
smd 0.25 x 0.35: 6 -0.5,-1.225; 7 0,-1.225; 8 0.5,-1.225; 14 0.5,1.225; 15 0,1.225; 16 -0.5,1.225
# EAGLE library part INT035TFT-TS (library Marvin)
Displaytech INT035TFT-TS QVGA full color display with touch-screen

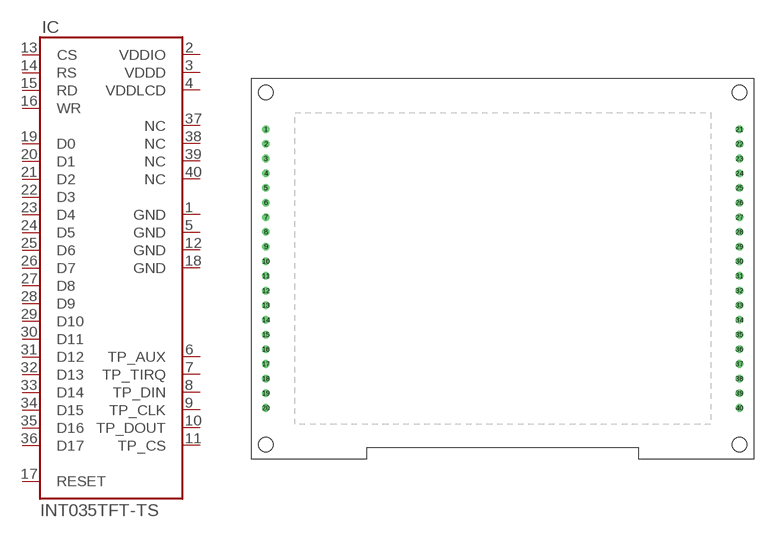
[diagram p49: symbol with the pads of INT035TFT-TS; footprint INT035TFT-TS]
Designator prefix IC

## INT035TFT-TS  [INT035TFT-TS]
1  GND  pwr
2  VDDIO  pwr
3  VDDD  pwr
4  VDDLCD  pwr
5  GND  pwr
6  TP_AUX
7  TP_TIRQ
8  TP_DIN
9  TP_CLK
10  TP_DOUT
11  TP_CS
12  GND  pwr
13  CS
14  RS
15  RD
16  WR
17  RESET
18  GND  pwr
19  D0
20  D1
21  D2
22  D3
23  D4
24  D5
25  D6
26  D7
27  D8
28  D9
29  D10
30  D11
31  D12
32  D13
33  D14
34  D15
35  D16
36  D17
37  NC  nc
38  NC  nc
39  NC  nc
40  NC  nc

## Footprint INT035TFT-TS (pad centres in mm)
Displaytech INT035TFT-TS QVGA
drill 0.8 round: 1 -41,24.13; 2 -41,21.59; 3 -41,19.05; 4 -41,16.51; 5 -41,13.97; 6 -41,11.43; 7 -41,8.89; 8 -41,6.35; 9 -41,3.81; 10 -41,1.27; 11 -41,-1.27; 12 -41,-3.81; 13 -41,-6.35; 14 -41,-8.89; 15 -41,-11.43; 16 -41,-13.97; 17 -41,-16.51; 18 -41,-19.05; 19 -41,-21.59; 20 -41,-24.13; 21 41,24.13; 22 41,21.59; 23 41,19.05; 24 41,16.51; 25 41,13.97; 26 41,11.43; 27 41,8.89; 28 41,6.35; 29 41,3.81; 30 41,1.27; 31 41,-1.27; 32 41,-3.81; 33 41,-6.35; 34 41,-8.89; 35 41,-11.43; 36 41,-13.97; 37 41,-16.51; 38 41,-19.05; 39 41,-21.59; 40 41,-24.13
hole 2.5 at -41,30.5
hole 2.5 at 41,30.5
hole 2.5 at 41,-30.5
hole 2.5 at -41,-30.5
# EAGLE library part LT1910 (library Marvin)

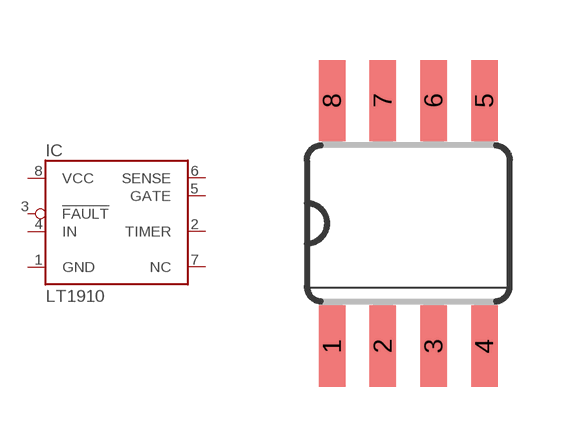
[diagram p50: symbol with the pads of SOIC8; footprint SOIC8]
Designator prefix IC

## LT1910  [SOIC8]
1  GND  pwr
2  TIMER
3  !FAULT
4  IN
5  GATE
6  SENSE
7  NC
8  VCC  pwr

## Footprint SOIC8 (pad centres in mm)
smd 0.66 x 2.032: 1 -1.905,-3.073; 2 -0.635,-3.073; 3 0.635,-3.073; 4 1.905,-3.073; 5 1.905,3.073; 6 0.635,3.073; 7 -0.635,3.073; 8 -1.905,3.073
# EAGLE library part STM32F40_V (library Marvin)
168 MHz, 192KB RAM, 1024 KB Flash

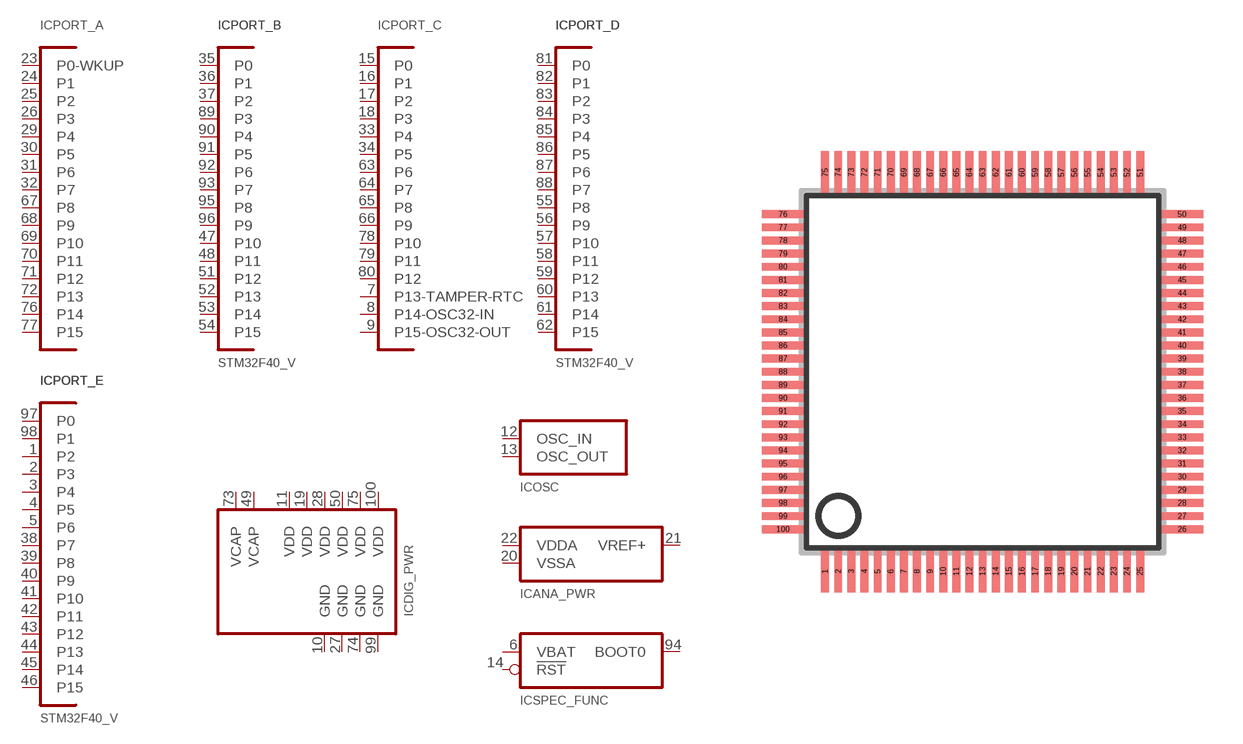
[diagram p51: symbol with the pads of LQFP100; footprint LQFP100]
Designator prefix IC; gates PORT_A=IO_PORT_A PORT_C=IO_PORT_C PORT_B=IO_PORT PORT_D=IO_PORT PORT_E=IO_PORT OSC=OSC ANA_PWR=ANA_PWR40_Z DIG_PWR=DIG_PWR40_V SPEC_FUNC=SPEC_FUNC40V

## STM32F40_V  [LQFP100]
1  PORT_E:P2
2  PORT_E:P3
3  PORT_E:P4
4  PORT_E:P5
5  PORT_E:P6
6  SPEC_FUNC:VBAT  pas
7  PORT_C:P13-TAMPER-RTC
8  PORT_C:P14-OSC32-IN
9  PORT_C:P15-OSC32-OUT
10  DIG_PWR:GND  pwr
11  DIG_PWR:VDD  pwr
12  OSC:OSC_IN  pas
13  OSC:OSC_OUT  pas
14  SPEC_FUNC:!RST  in
15  PORT_C:P0
16  PORT_C:P1
17  PORT_C:P2
18  PORT_C:P3
19  DIG_PWR:VDD  pwr
20  ANA_PWR:VSSA  pwr
21  ANA_PWR:VREF+  pas
22  ANA_PWR:VDDA  pwr
23  PORT_A:P0-WKUP
24  PORT_A:P1
25  PORT_A:P2
26  PORT_A:P3
27  DIG_PWR:GND  pwr
28  DIG_PWR:VDD  pwr
29  PORT_A:P4
30  PORT_A:P5
31  PORT_A:P6
32  PORT_A:P7
33  PORT_C:P4
34  PORT_C:P5
35  PORT_B:P0
36  PORT_B:P1
37  PORT_B:P2
38  PORT_E:P7
39  PORT_E:P8
40  PORT_E:P9
41  PORT_E:P10
42  PORT_E:P11
43  PORT_E:P12
44  PORT_E:P13
45  PORT_E:P14
46  PORT_E:P15
47  PORT_B:P10
48  PORT_B:P11
49  DIG_PWR:VCAP  pwr
50  DIG_PWR:VDD  pwr
51  PORT_B:P12
52  PORT_B:P13
53  PORT_B:P14
54  PORT_B:P15
55  PORT_D:P8
56  PORT_D:P9
57  PORT_D:P10
58  PORT_D:P11
59  PORT_D:P12
60  PORT_D:P13
61  PORT_D:P14
62  PORT_D:P15
63  PORT_C:P6
64  PORT_C:P7
65  PORT_C:P8
66  PORT_C:P9
67  PORT_A:P8
68  PORT_A:P9
69  PORT_A:P10
70  PORT_A:P11
71  PORT_A:P12
72  PORT_A:P13
73  DIG_PWR:VCAP  pwr
74  DIG_PWR:GND  pwr
75  DIG_PWR:VDD  pwr
76  PORT_A:P14
77  PORT_A:P15
78  PORT_C:P10
79  PORT_C:P11
80  PORT_C:P12
81  PORT_D:P0
82  PORT_D:P1
83  PORT_D:P2
84  PORT_D:P3
85  PORT_D:P4
86  PORT_D:P5
87  PORT_D:P6
88  PORT_D:P7
89  PORT_B:P3
90  PORT_B:P4
91  PORT_B:P5
92  PORT_B:P6
93  PORT_B:P7
94  SPEC_FUNC:BOOT0  in
95  PORT_B:P8
96  PORT_B:P9
97  PORT_E:P0
98  PORT_E:P1
99  DIG_PWR:GND  pwr
100  DIG_PWR:VDD  pwr

## Footprint LQFP100 (pad centres in mm)
QFP100 shrink quad flat pack, square
smd 0.3 x 1.6: 1 -6,-7.6; 2 -5.5,-7.6; 3 -5,-7.6; 4 -4.5,-7.6; 5 -4,-7.6; 6 -3.5,-7.6; 7 -3,-7.6; 8 -2.5,-7.6; 9 -2,-7.6; 10 -1.5,-7.6; 11 -1,-7.6; 12 -0.5,-7.6; 13 0,-7.6; 14 0.5,-7.6; 15 1,-7.6; 16 1.5,-7.6; 17 2,-7.6; 18 2.5,-7.6; 19 3,-7.6; 20 3.5,-7.6; 21 4,-7.6; 22 4.5,-7.6; 23 5,-7.6; 24 5.5,-7.6; 25 6,-7.6; 51 6,7.6; 52 5.5,7.6; 53 5,7.6; 54 4.5,7.6; 55 4,7.6; 56 3.5,7.6; 57 3,7.6; 58 2.5,7.6; 59 2,7.6; 60 1.5,7.6; 61 1,7.6; 62 0.5,7.6; 63 0,7.6; 64 -0.5,7.6; 65 -1,7.6; 66 -1.5,7.6; 67 -2,7.6; 68 -2.5,7.6; 69 -3,7.6; 70 -3.5,7.6; 71 -4,7.6; 72 -4.5,7.6; 73 -5,7.6; 74 -5.5,7.6; 75 -6,7.6
smd 1.6 x 0.3: 26 7.6,-6; 27 7.6,-5.5; 28 7.6,-5; 29 7.6,-4.5; 30 7.6,-4; 31 7.6,-3.5; 32 7.6,-3; 33 7.6,-2.5; 34 7.6,-2; 35 7.6,-1.5; 36 7.6,-1; 37 7.6,-0.5; 38 7.6,0; 39 7.6,0.5; 40 7.6,1; 41 7.6,1.5; 42 7.6,2; 43 7.6,2.5; 44 7.6,3; 45 7.6,3.5; 46 7.6,4; 47 7.6,4.5; 48 7.6,5; 49 7.6,5.5; 50 7.6,6; 76 -7.6,6; 77 -7.6,5.5; 78 -7.6,5; 79 -7.6,4.5; 80 -7.6,4; 81 -7.6,3.5; 82 -7.6,3; 83 -7.6,2.5; 84 -7.6,2; 85 -7.6,1.5; 86 -7.6,1; 87 -7.6,0.5; 88 -7.6,0; 89 -7.6,-0.5; 90 -7.6,-1; 91 -7.6,-1.5; 92 -7.6,-2; 93 -7.6,-2.5; 94 -7.6,-3; 95 -7.6,-3.5; 96 -7.6,-4; 97 -7.6,-4.5; 98 -7.6,-5; 99 -7.6,-5.5; 100 -7.6,-6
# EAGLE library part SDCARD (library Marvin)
TE Connectivity 2041021-3 SD Card Socket Farnell Order Number: 2112526

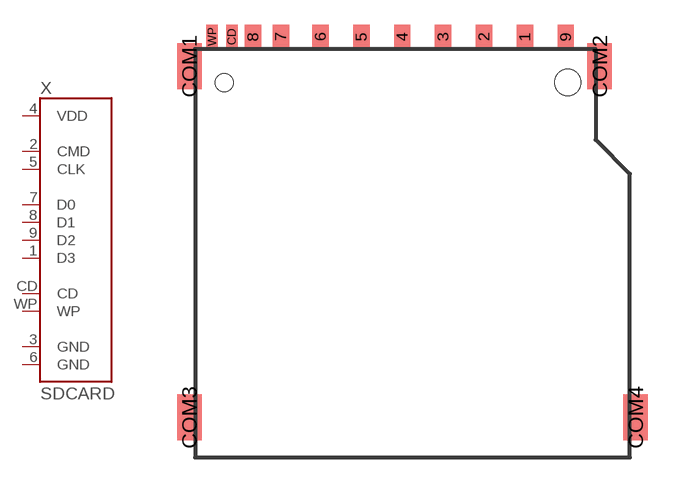
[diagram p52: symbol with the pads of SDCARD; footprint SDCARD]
Designator prefix X

## SDCARD  [SDCARD]
1  D3
2  CMD
3  GND
4  VDD
5  CLK
6  GND
7  D0
8  D1
9  D2
CD  CD
WP  WP

## Footprint SDCARD (pad centres in mm)
smd 1 x 1.5: 1 6.875,0.75; 2 4.375,0.75; 3 1.875,0.75; 4 -0.625,0.75; 5 -3.125,0.75; 6 -5.625,0.75; 7 -8.05,0.75; 8 -9.75,0.75; 9 9.375,0.75
smd 0.7 x 1.5: CD -11.05,0.75; WP -12.25,0.75
smd 1.5 x 2.8: COM1 -13.65,-1.05; COM2 11.45,-1.05; COM3 -13.65,-22.55; COM4 13.65,-22.55
hole 1.1 at -11.5,-2.05
hole 1.6 at 9.5,-2.05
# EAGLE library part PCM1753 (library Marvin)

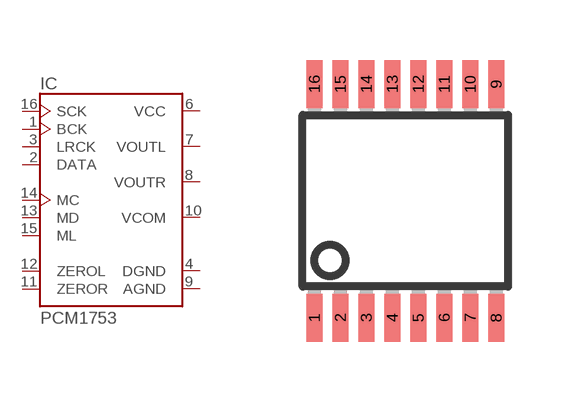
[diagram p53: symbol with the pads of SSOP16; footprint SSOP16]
Designator prefix IC

## PCM1753  [SSOP16]
1  BCK
2  DATA
3  LRCK
4  DGND  pwr
6  VCC  pwr
7  VOUTL
8  VOUTR
9  AGND  pwr
10  VCOM  pas
11  ZEROR
12  ZEROL
13  MD
14  MC
15  ML
16  SCK

## Footprint SSOP16 (pad centres in mm)
Small Shrink Outline Package
smd 0.4 x 1.2: 1 -2.275,-2.925; 2 -1.625,-2.925; 3 -0.975,-2.925; 4 -0.325,-2.925; 5 0.325,-2.925; 6 0.975,-2.925; 7 1.625,-2.925; 8 2.275,-2.925; 9 2.275,2.925; 10 1.625,2.925; 11 0.975,2.925; 12 0.325,2.925; 13 -0.325,2.925; 14 -0.975,2.925; 15 -1.625,2.925; 16 -2.275,2.925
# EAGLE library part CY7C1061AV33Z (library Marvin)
1M x 16 Static RAM Source: CYPRESS cy7c1061av33_8.pdf

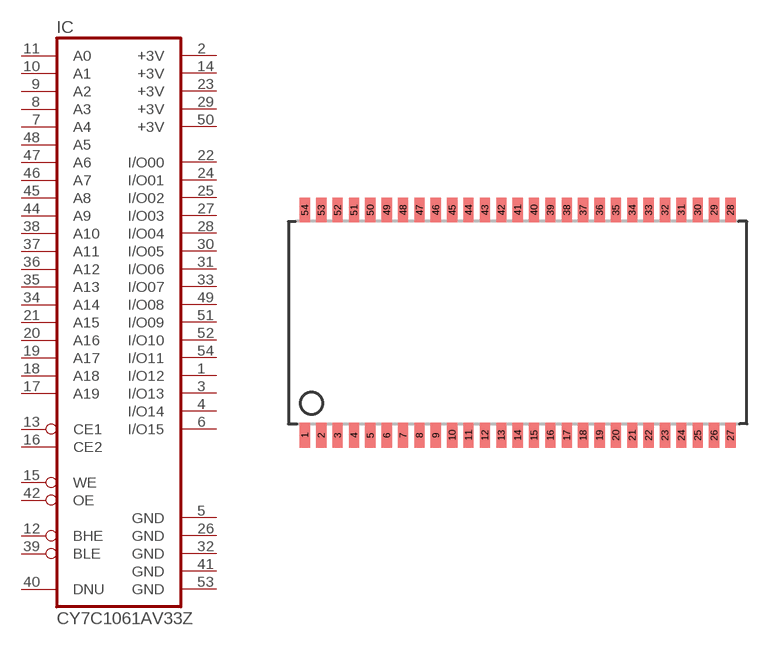
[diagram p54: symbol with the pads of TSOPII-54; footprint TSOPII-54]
Designator prefix IC

## CY7C1061AV33Z  [TSOPII-54]
1  I/O12
2  +3V  pwr
3  I/O13
4  I/O14
5  GND  pwr
6  I/O15
7  A4  in
8  A3  in
9  A2  in
10  A1  in
11  A0  in
12  BHE  in
13  CE1  in
14  +3V  pwr
15  WE  in
16  CE2  in
17  A19  in
18  A18  in
19  A17  in
20  A16  in
21  A15  in
22  I/O00
23  +3V  pwr
24  I/O01
25  I/O02
26  GND  pwr
27  I/O03
28  I/O04
29  +3V  pwr
30  I/O05
31  I/O06
32  GND  pwr
33  I/O07
34  A14  in
35  A13  in
36  A12  in
37  A11  in
38  A10  in
39  BLE  in
40  DNU  pas
41  GND  pwr
42  OE  in
44  A9  in
45  A8  in
46  A7  in
47  A6  in
48  A5  in
49  I/O08
50  +3V  pwr
51  I/O09
52  I/O10
53  GND  pwr
54  I/O11

## Footprint TSOPII-54 (pad centres in mm)
54-pin TSOP II (51-85160) Source: CYPRESS cy7c1069av33_8.pdf
smd 0.5 x 1.2: 1 -10.4,-5.502; 2 -9.6,-5.502; 3 -8.8,-5.502; 4 -8,-5.502; 5 -7.2,-5.502; 6 -6.4,-5.502; 7 -5.6,-5.502; 8 -4.8,-5.502; 9 -4,-5.502; 10 -3.2,-5.502; 11 -2.4,-5.502; 12 -1.6,-5.502; 13 -0.8,-5.502; 14 0,-5.502; 15 0.8,-5.502; 16 1.6,-5.502; 17 2.4,-5.502; 18 3.2,-5.502; 19 4,-5.502; 20 4.8,-5.502; 21 5.6,-5.502; 22 6.4,-5.502; 23 7.2,-5.502; 24 8,-5.502; 25 8.8,-5.502; 26 9.6,-5.502; 27 10.4,-5.502; 28 10.4,5.502; 29 9.6,5.502; 30 8.8,5.502; 31 8,5.502; 32 7.2,5.502; 33 6.4,5.502; 34 5.6,5.502; 35 4.8,5.502; 36 4,5.502; 37 3.2,5.502; 38 2.4,5.502; 39 1.6,5.502; 40 0.8,5.502; 41 0,5.502; 42 -0.8,5.502; 43 -1.6,5.502; 44 -2.4,5.502; 45 -3.2,5.502; 46 -4,5.502; 47 -4.8,5.502; 48 -5.6,5.502; 49 -6.4,5.502; 50 -7.2,5.502; 51 -8,5.502; 52 -8.8,5.502; 53 -9.6,5.502; 54 -10.4,5.502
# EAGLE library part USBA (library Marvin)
Multicomp connector Farnell: 2112370

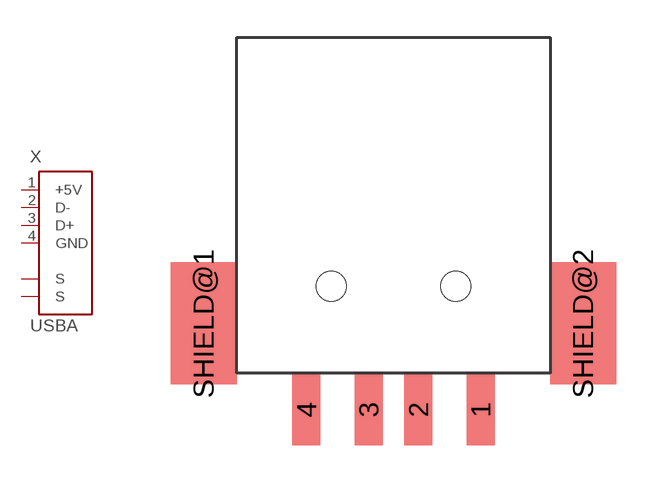
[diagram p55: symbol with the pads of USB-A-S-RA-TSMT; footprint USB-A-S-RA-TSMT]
Designator prefix X

## USBA  [USB-A-S-RA-TSMT]
1  +5V  pas
2  D-  pas
3  D+  pas
4  GND  pas
SHIELD@1  S  pas
SHIELD@2  S  pas

## Footprint USB-A-S-RA-TSMT (pad centres in mm)
smd 1.12 x 2.88: 1 3.5,-4.96; 2 1,-4.96; 3 -1,-4.96; 4 -3.5,-4.96
smd 2.65 x 4.9: SHIELD@1 -7.625,-1.5; SHIELD@2 7.625,-1.5
hole 1.2 at -2.5,0
hole 1.2 at 2.5,0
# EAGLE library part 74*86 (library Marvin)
Quad 2-input EXCLUSIVE-OR (XOR) gate

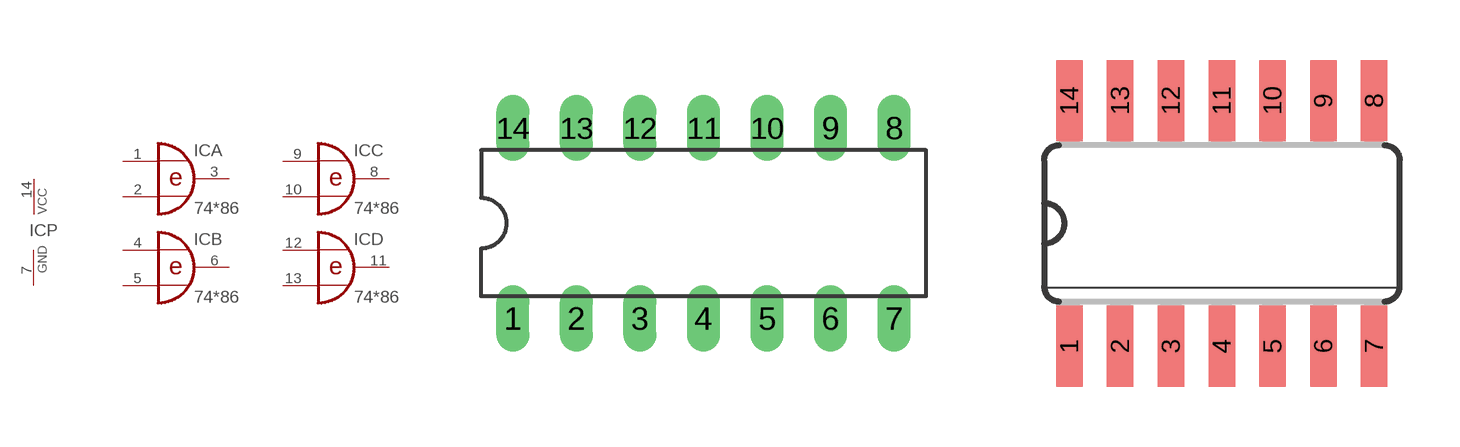
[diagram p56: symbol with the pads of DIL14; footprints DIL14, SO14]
Designator prefix IC; gates A=7486 B=7486 C=7486 D=7486 P=PWRN

## 7486N, 74AC86N, 74ACT86N, 74HC86N, 74HCT86N, 74LS86N, 74S86N  [DIL14]
1  A:I0  in
2  A:I1  in
3  A:O  out
4  B:I0  in
5  B:I1  in
6  B:O  out
7  P:GND  pwr
8  C:O  out
9  C:I0  in
10  C:I1  in
11  D:O  out
12  D:I0  in
13  D:I1  in
14  P:VCC  pwr

## 74AC86D, 74ACT86D, 74HC86D, 74HCT86D, 74LS86D, 74S86D  [SO14]
Pads as for DIL14

## 74AC86FK, 74ACT86FK, 74HC86FK, 74HCT86FK, 74LS86FK, 74S86FK  [LCC20]
2  A:I0  in
3  A:I1  in
4  A:O  out
6  B:I0  in
8  B:I1  in
9  B:O  out
10  P:GND  pwr
12  C:O  out
13  C:I0  in
14  C:I1  in
16  D:O  out
18  D:I0  in
19  D:I1  in
20  P:VCC  pwr

## 7486PW  [TSSOP14]
Pads as for DIL14

## Footprint DIL14 (pad centres in mm)
Dual In Line Package
drill 0.813 long: 1 -7.62,-3.81; 2 -5.08,-3.81; 3 -2.54,-3.81; 4 0,-3.81; 5 2.54,-3.81; 6 5.08,-3.81; 7 7.62,-3.81; 8 7.62,3.81; 9 5.08,3.81; 10 2.54,3.81; 11 0,3.81; 12 -2.54,3.81; 13 -5.08,3.81; 14 -7.62,3.81

## Footprint SO14 (pad centres in mm)
Small Outline package 150 mil
smd 0.66 x 2.032: 1 -3.81,-3.073; 2 -2.54,-3.073; 3 -1.27,-3.073; 4 0,-3.073; 5 1.27,-3.073; 6 2.54,-3.073; 7 3.81,-3.073; 8 3.81,3.073; 9 2.54,3.073; 10 1.27,3.073; 11 0,3.073; 12 -1.27,3.073; 13 -2.54,3.073; 14 -3.81,3.073

## Footprint LCC20 (pad centres in mm)
Leadless Chip Carrier Ceramic Package
smd 0.8 x 3.4: 1 0,3.8
smd 0.8 x 2: 2 -1.27,4.5; 3 -2.54,4.5; 9 -2.54,-4.5; 10 -1.27,-4.5; 11 0,-4.5; 12 1.27,-4.5; 13 2.54,-4.5; 19 2.54,4.5; 20 1.27,4.5
smd 2 x 0.8: 4 -4.5,2.54; 5 -4.5,1.27; 6 -4.5,0; 7 -4.5,-1.27; 8 -4.5,-2.54; 14 4.5,-2.54; 15 4.5,-1.27; 16 4.5,0; 17 4.5,1.27; 18 4.5,2.54

## Footprint TSSOP14 (pad centres in mm)
smd 0.305 x 0.991: 1 -1.95,-2.918; 2 -1.3,-2.918; 3 -0.65,-2.918; 4 0,-2.918; 5 0.65,-2.918; 6 1.3,-2.918; 7 1.95,-2.918; 8 1.95,2.918; 9 1.3,2.918; 10 0.65,2.918; 11 0,2.918; 12 -0.65,2.918; 13 -1.3,2.918; 14 -1.95,2.918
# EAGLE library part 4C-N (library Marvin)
Array Chip Capacitor

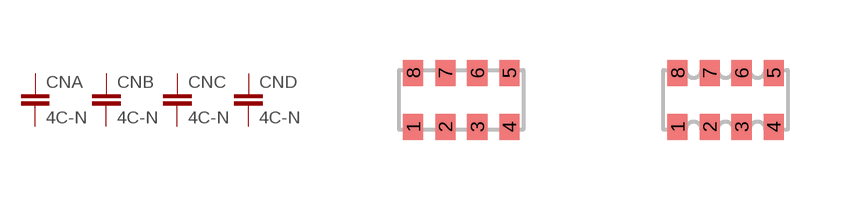
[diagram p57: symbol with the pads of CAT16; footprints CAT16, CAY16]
Designator prefix CN; gates C=C-EU D=C-EU A=C-EU B=C-EU

## 4C-NCAT16 (OC_FARNELL: unknown; OC_NEWARK: unknown)  [CAT16]
1  A:1  pas
2  B:1  pas
3  C:1  pas
4  D:1  pas
5  D:2  pas
6  C:2  pas
7  B:2  pas
8  A:2  pas

## 4C-NCAY16 (OC_FARNELL: unknown; OC_NEWARK: unknown)  [CAY16]
Pads as for CAT16

## Footprint CAT16 (pad centres in mm)
BOURNS Chip Resistor Array Source: RS Component / BUORNS
smd 0.5 x 0.65: 1 -1.2,-0.675; 2 -0.4,-0.675; 3 0.4,-0.675; 4 1.2,-0.675; 5 1.2,0.675; 6 0.4,0.675; 7 -0.4,0.675; 8 -1.2,0.675

## Footprint CAY16 (pad centres in mm)
BOURNS Chip Resistor Array Source: RS Component / BUORNS
smd 0.5 x 0.65: 1 -1.2,-0.675; 2 -0.4,-0.675; 3 0.4,-0.675; 4 1.2,-0.675; 5 1.2,0.675; 6 0.4,0.675; 7 -0.4,0.675; 8 -1.2,0.675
